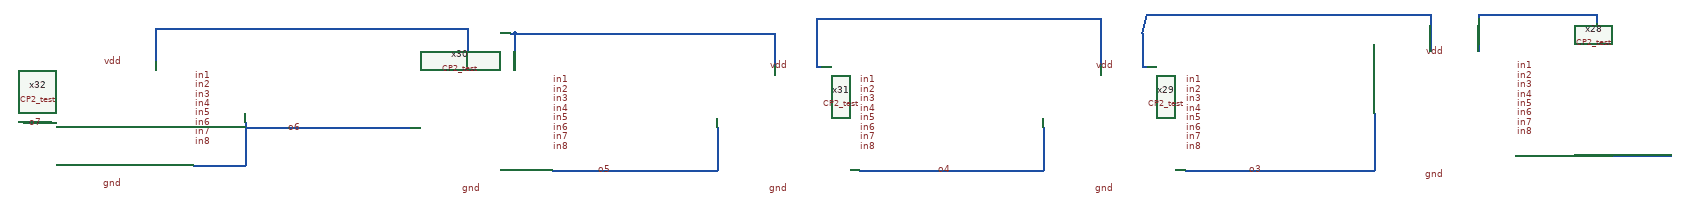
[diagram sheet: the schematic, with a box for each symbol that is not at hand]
v {xschem version=3.4.4 file_version=1.2
}
G {}
K {}
V {}
S {}
E {}
N 1400 -170 1400 -150 {
lab=#net1}
N 710 -170 710 -150 {
lab=#net2}
N -950 -30 -910 -30 {
lab=o7}
N -500 -30 -500 60 {
lab=o6}
N 710 -230 710 -170 {
lab=#net2}
N 2110 -240 2110 -180 {
lab=#net3}
N 1400 -150 1410 -150 {
lab=#net1}
N 710 -150 720 -150 {
lab=#net2}
N -610 60 -500 60 {
lab=o6}
N -500 -20 -150 -20 {
lab=o6}
N 150 70 500 70 {
lab=o5}
N 500 -20 500 70 {
lab=o5}
N 800 70 1190 70 {
lab=o4}
N 1190 -20 1190 70 {
lab=o4}
N 1490 70 1890 70 {
lab=o3}
N 1890 -50 1890 70 {
lab=o3}
N 2190 40 2280 40 {
lab=#net4}
N 2280 40 2520 40 {
lab=#net4}
N -970 -30 -950 -30 {
lab=o7}
N 60 -220 70 -220 {
lab=#net5}
N 70 -220 70 -160 {
lab=#net5}
N 70 -180 70 -140 {
lab=#net5}
N 710 -250 710 -230 {
lab=#net2}
N 1400 -220 1400 -170 {
lab=#net1}
N 2110 -250 2110 -230 {
lab=#net3}
N 2360 -260 2360 -240 {
lab=#net3}
N 2110 -260 2360 -260 {
lab=#net3}
N 2110 -260 2110 -240 {
lab=#net3}
N 2010 -260 2010 -180 {
lab=#net1}
N 1410 -260 2010 -260 {
lab=#net1}
N 1400 -220 1410 -260 {
lab=#net1}
N 710 -250 1310 -250 {
lab=#net2}
N 1310 -250 1310 -150 {
lab=#net2}
N 70 -220 620 -220 {
lab=#net5}
N 620 -220 620 -150 {
lab=#net5}
N -690 -230 -690 -160 {
lab=#net6}
N -690 -230 -30 -230 {
lab=#net6}
N -30 -230 -30 -150 {
lab=#net6}
C {devices/lab_pin.sym} 2040 -180 3 1 {name=p216 sig_type=std_logic lab=vdd}
C {devices/lab_pin.sym} 2190 -150 0 1 {name=p218 sig_type=std_logic lab=in1
value=0}
C {devices/lab_pin.sym} 2190 -130 0 1 {name=p219 sig_type=std_logic lab=in2
value=0}
C {devices/lab_pin.sym} 2190 -110 0 1 {name=p220 sig_type=std_logic lab=in3
value=0}
C {devices/lab_pin.sym} 2190 -90 0 1 {name=p221 sig_type=std_logic lab=in4
value=0}
C {devices/lab_pin.sym} 2190 -70 0 1 {name=p222 sig_type=std_logic lab=in5
value=0}
C {devices/lab_pin.sym} 2190 -50 0 1 {name=p223 sig_type=std_logic lab=in6
value=0}
C {devices/lab_pin.sym} 2190 -30 0 1 {name=p224 sig_type=std_logic lab=in7
value=0}
C {devices/lab_pin.sym} 2190 -10 0 1 {name=p225 sig_type=std_logic lab=in8
value=0}
C {devices/lab_pin.sym} 2040 80 1 1 {name=p227 sig_type=std_logic lab=gnd}
C {devices/lab_pin.sym} 1340 -150 3 1 {name=p232 sig_type=std_logic lab=vdd}
C {devices/lab_pin.sym} 1490 -120 0 1 {name=p233 sig_type=std_logic lab=in1
value=0}
C {devices/lab_pin.sym} 1490 -100 0 1 {name=p234 sig_type=std_logic lab=in2
value=0}
C {devices/lab_pin.sym} 1490 -80 0 1 {name=p235 sig_type=std_logic lab=in3
value=0}
C {devices/lab_pin.sym} 1490 -60 0 1 {name=p236 sig_type=std_logic lab=in4
value=0}
C {devices/lab_pin.sym} 1490 -40 0 1 {name=p237 sig_type=std_logic lab=in5
value=0}
C {devices/lab_pin.sym} 1490 -20 0 1 {name=p238 sig_type=std_logic lab=in6
value=0}
C {devices/lab_pin.sym} 1490 0 0 1 {name=p239 sig_type=std_logic lab=in7
value=0}
C {devices/lab_pin.sym} 1490 20 0 1 {name=p240 sig_type=std_logic lab=in8
value=0}
C {devices/lab_pin.sym} 1340 110 1 1 {name=p241 sig_type=std_logic lab=gnd}
C {devices/lab_pin.sym} 650 -150 3 1 {name=p246 sig_type=std_logic lab=vdd}
C {devices/lab_pin.sym} 800 -120 0 1 {name=p247 sig_type=std_logic lab=in1
value=0}
C {devices/lab_pin.sym} 800 -100 0 1 {name=p248 sig_type=std_logic lab=in2
value=0}
C {devices/lab_pin.sym} 800 -80 0 1 {name=p249 sig_type=std_logic lab=in3
value=0}
C {devices/lab_pin.sym} 800 -60 0 1 {name=p250 sig_type=std_logic lab=in4
value=0}
C {devices/lab_pin.sym} 800 -40 0 1 {name=p251 sig_type=std_logic lab=in5
value=0}
C {devices/lab_pin.sym} 800 -20 0 1 {name=p252 sig_type=std_logic lab=in6
value=0}
C {devices/lab_pin.sym} 800 0 0 1 {name=p253 sig_type=std_logic lab=in7
value=0}
C {devices/lab_pin.sym} 800 20 0 1 {name=p254 sig_type=std_logic lab=in8
value=0}
C {devices/lab_pin.sym} 650 110 1 1 {name=p255 sig_type=std_logic lab=gnd}
C {devices/lab_pin.sym} 0 -150 3 1 {name=p260 sig_type=std_logic lab=vdd}
C {devices/lab_pin.sym} 150 -120 0 1 {name=p261 sig_type=std_logic lab=in1
value=0}
C {devices/lab_pin.sym} 150 -100 0 1 {name=p262 sig_type=std_logic lab=in2
value=0}
C {devices/lab_pin.sym} 150 -80 0 1 {name=p263 sig_type=std_logic lab=in3
value=0}
C {devices/lab_pin.sym} 150 -60 0 1 {name=p264 sig_type=std_logic lab=in4
value=0}
C {devices/lab_pin.sym} 150 -40 0 1 {name=p265 sig_type=std_logic lab=in5
value=0}
C {devices/lab_pin.sym} 150 -20 0 1 {name=p266 sig_type=std_logic lab=in6
value=0}
C {devices/lab_pin.sym} 150 0 0 1 {name=p267 sig_type=std_logic lab=in7
value=0}
C {devices/lab_pin.sym} 150 20 0 1 {name=p268 sig_type=std_logic lab=in8
value=0}
C {devices/lab_pin.sym} 0 110 1 1 {name=p269 sig_type=std_logic lab=gnd}
C {devices/lab_pin.sym} -760 -160 3 1 {name=p274 sig_type=std_logic lab=vdd}
C {devices/lab_pin.sym} -610 -130 0 1 {name=p275 sig_type=std_logic lab=in1
value=0}
C {devices/lab_pin.sym} -610 -110 0 1 {name=p276 sig_type=std_logic lab=in2
value=0}
C {devices/lab_pin.sym} -610 -90 0 1 {name=p277 sig_type=std_logic lab=in3
value=0}
C {devices/lab_pin.sym} -610 -70 0 1 {name=p278 sig_type=std_logic lab=in4
value=0}
C {devices/lab_pin.sym} -610 -50 0 1 {name=p279 sig_type=std_logic lab=in5
value=0}
C {devices/lab_pin.sym} -610 -30 0 1 {name=p280 sig_type=std_logic lab=in6
value=0}
C {devices/lab_pin.sym} -610 -10 0 1 {name=p281 sig_type=std_logic lab=in7
value=0}
C {devices/lab_pin.sym} -610 10 0 1 {name=p282 sig_type=std_logic lab=in8
value=0}
C {devices/lab_pin.sym} -760 100 1 1 {name=p283 sig_type=std_logic lab=gnd}
C {CP2_test.sym} 2040 -50 0 1 {name=x28}
C {CP2_test.sym} 1340 -20 0 1 {name=x29}
C {CP2_test.sym} 0 -20 0 1 {name=x30}
C {CP2_test.sym} 650 -20 0 1 {name=x31}
C {CP2_test.sym} -760 -30 0 1 {name=x32}
C {devices/lab_pin.sym} 1655 70 3 0 {name=p634 sig_type=std_logic lab=o3}
C {devices/lab_pin.sym} 995 70 3 0 {name=p635 sig_type=std_logic lab=o4}
C {devices/lab_pin.sym} 275 70 3 0 {name=p638 sig_type=std_logic lab=o5}
C {devices/lab_pin.sym} -380 -20 3 0 {name=p639 sig_type=std_logic lab=o6}
C {devices/lab_pin.sym} -930 -30 3 0 {name=p641 sig_type=std_logic lab=o7}
